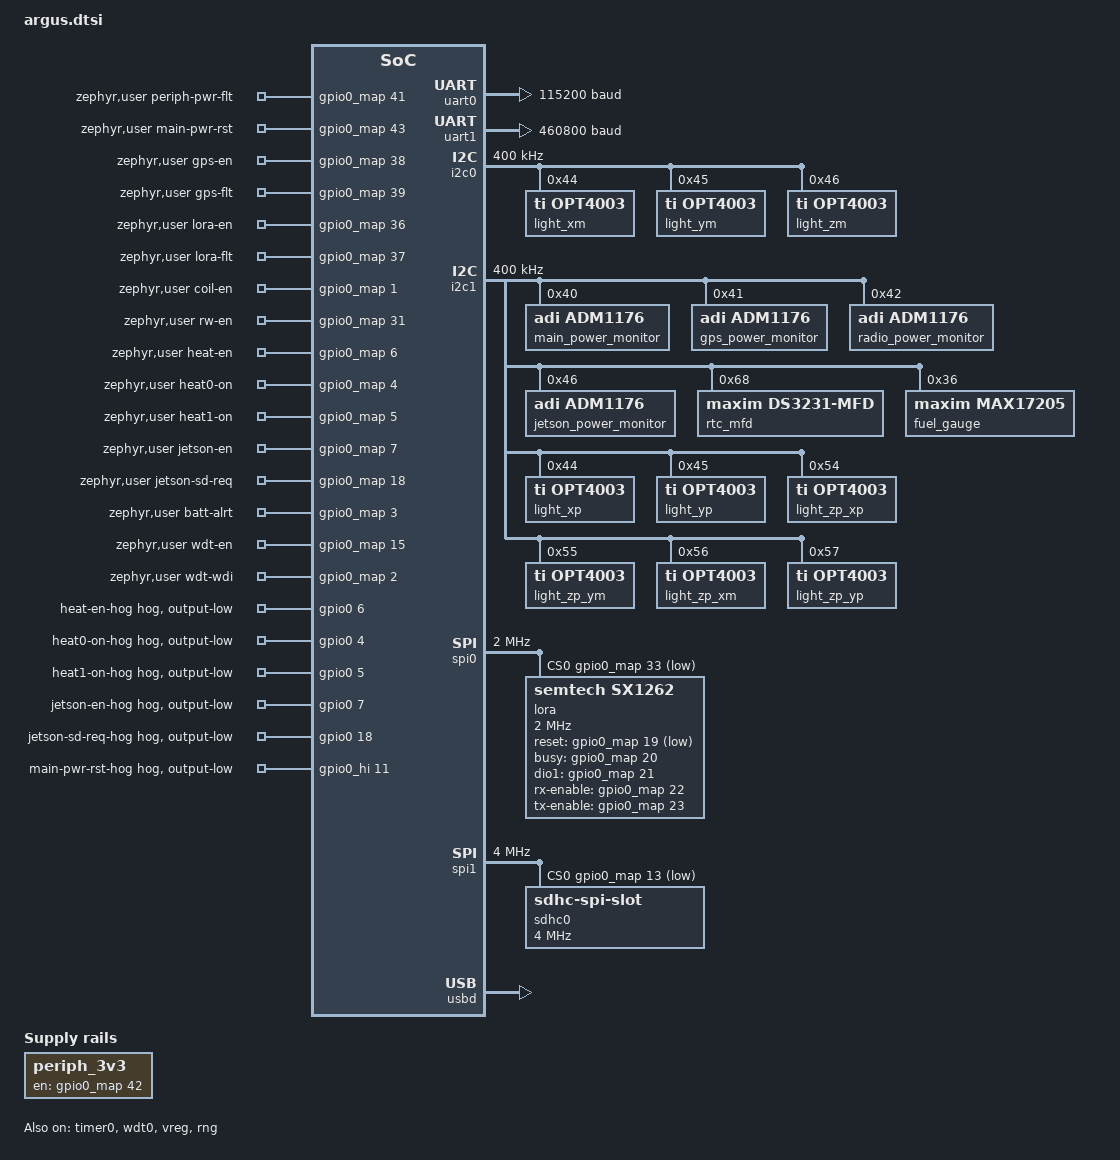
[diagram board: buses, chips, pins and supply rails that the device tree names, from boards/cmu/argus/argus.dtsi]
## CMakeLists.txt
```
cmake_minimum_required(VERSION 3.20.0)

# Default target (current default hardware revision is set in boards/cmu/argus/board.yml).
# Pick a revision explicitly with e.g. `west build -b argus@4/rp2350b/m33_0`.
set(BOARD argus/rp2350b/m33_0)

list(APPEND BOARD_ROOT ${CMAKE_CURRENT_SOURCE_DIR})
find_package(Zephyr REQUIRED HINTS $ENV{ZEPHYR_BASE})
project(FSW-Mainboard-C)

target_sources(app PRIVATE
        src/main.c
        src/drivers/adm1176.c
        src/drivers/drv8235.c
        src/drivers/max17205.c
        src/drivers/opt4003.c
        src/apps/eps/eps.c
        src/tasks/eps.c
        src/tasks/eps_runner.c
)

target_include_directories(app PRIVATE
        ${CMAKE_CURRENT_LIST_DIR}/include
)

# Generate argus_version.h (git hash + dirty flag) on every build, so the
# version printed at boot is never stale.
set(ARGUS_VERSION_DIR ${CMAKE_BINARY_DIR}/include/generated/argus)
add_custom_target(argus_version_h
        COMMAND ${CMAKE_COMMAND}
                -DSRC_DIR=${CMAKE_CURRENT_SOURCE_DIR}
                -DOUT_FILE=${ARGUS_VERSION_DIR}/argus_version.h
                -P ${CMAKE_CURRENT_SOURCE_DIR}/cmake/gen_version.cmake
        BYPRODUCTS ${ARGUS_VERSION_DIR}/argus_version.h
)
add_dependencies(app argus_version_h)
target_include_directories(app PRIVATE ${ARGUS_VERSION_DIR})
```

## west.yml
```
# West manifest: pins the Zephyr version and the modules this project uses.
# Set up a workspace with:
#   west init -m https://github.com/cmu-argus-2/FSW-Mainboard-C --mr main <workspace-dir>
#   cd <workspace-dir> && west update

manifest:
  remotes:
    - name: zephyrproject-rtos
      url-base: https://github.com/zephyrproject-rtos

  projects:
    - name: zephyr
      remote: zephyrproject-rtos
      revision: 839728050444f90d06870b5fc9bbbda106d91459
      import:
        name-allowlist:
          - cmsis_6       # Cortex-M33 core support
          - hal_rpi_pico  # RP2350 drivers
          - fatfs         # SD card filesystem
          - littlefs      # on-board flash storage
          - loramac-node  # SX1262 radio backend

  self:
    path: FSW-Mainboard-C
```

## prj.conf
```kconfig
CONFIG_LED_STRIP=y
CONFIG_I2C=y
CONFIG_FUEL_GAUGE=y
CONFIG_MAIN_STACK_SIZE=4096
CONFIG_HW_STACK_PROTECTION=y
CONFIG_SENSOR=y
# The RP2350 die-temperature node is enabled by the SoC DTS, but the Argus
# board does not enable its ADC. It is unrelated to the external ADM1176s.
CONFIG_RPI_PICO_TEMP=n
CONFIG_LOG=y
```

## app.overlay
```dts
/* SPDX-License-Identifier: Apache-2.0 */
/* EPS consumes the SoC die-temperature sensor via the ADC. */
&adc {
	status = "okay";
};

&die_temp {
	status = "okay";
};
```

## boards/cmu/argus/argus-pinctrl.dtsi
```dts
/*
 * SPDX-License-Identifier: Apache-2.0
 *
 * Revision 4 pin numbers from the Python flight software's
 * firmware/Mainboard v4/pins.c (the CircuitPython board definition).
 */

#include <zephyr/dt-bindings/pinctrl/rpi-pico-rp2350b-pinctrl.h>

&pinctrl {
	/* GPS: TX0/RX0 */
	uart0_default: uart0_default {
		group1 {
			pinmux = <UART0_TX_P44>;
		};

		group2 {
			pinmux = <UART0_RX_P45>;
			input-enable;
		};
	};

	/* Jetson: TX1/RX1 */
	uart1_default: uart1_default {
		group1 {
			pinmux = <UART1_TX_P8>;
		};

		group2 {
			pinmux = <UART1_RX_P9>;
			input-enable;
		};
	};

	/* Radio. CS (GPIO33) is a plain GPIO, see cs-gpios. */
	spi0_default: spi0_default {
		group1 {
			pinmux = <SPI0_SCK_P34>, <SPI0_TX_P35>;
		};

		group2 {
			pinmux = <SPI0_RX_P32>;
			input-enable;
		};
	};

	/* SD card. CS (GPIO13) is a plain GPIO, see cs-gpios. */
	spi1_default: spi1_default {
		group1 {
			pinmux = <SPI1_SCK_P10>, <SPI1_TX_P11>;
		};

		group2 {
			pinmux = <SPI1_RX_P12>;
			input-enable;
		};
	};

	/* -X/-Y/-Z faces, IMU */
	i2c0_default: i2c0_default {
		group1 {
			pinmux = <I2C0_SDA_P24>, <I2C0_SCL_P25>;
			input-enable;
			input-schmitt-enable;
		};
	};

	/* +X/+Y/+Z faces, RTC, fuel gauge, power monitors */
	i2c1_default: i2c1_default {
		group1 {
			pinmux = <I2C1_SDA_P46>, <I2C1_SCL_P47>;
			input-enable;
			input-schmitt-enable;
		};
	};

	ws2812_pio0_default: ws2812_pio0_default {
		ws2812 {
			pinmux = <PIO0_P0>;
		};
	};
};
```

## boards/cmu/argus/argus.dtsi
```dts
/*
 * SPDX-License-Identifier: Apache-2.0
 *
 * CMU Argus Mainboard: RP2350B, W25Q32JV (4 MiB) flash.
 *
 * These base files describe revision 4. Later revisions go in
 * argus_rp2350b_m33_0_<N>.overlay (see board.yml).
 *
 * Pin numbers come from the Python flight software's
 * firmware/Mainboard v4/pins.c and bus assignments from its
 * flight/hal/argus_v4.py.
 *
 * GPIOs are referenced through &gpio0_map, which takes the raw GPIO number
 * (0-47) and routes 32-47 to the high bank, so numbers match pins.c.
 */

#include <freq.h>

#include <zephyr/dt-bindings/i2c/i2c.h>
#include <zephyr/dt-bindings/led/led.h>
#include <zephyr/dt-bindings/lora/sx126x.h>

#include "argus-pinctrl.dtsi"

/ {
	chosen {
		zephyr,sram = &sram0;
		zephyr,flash = &flash0;
		zephyr,flash-controller = &qmi;
		zephyr,code-partition = &code_partition;
	};

	aliases {
		watchdog0 = &wdt0;
		led-strip = &neopixel;
		lora0 = &lora;
		gps-uart = &uart0;
		jetson-uart = &uart1;
	};

	/*
	 * Board control lines, read with GPIO_DT_SPEC_GET(DT_PATH(zephyr_user), <prop>).
	 * Enables are active-high (the Python HAL sets them True to turn things on).
	 * *-flt-gpios and batt-alrt-gpios are described at the raw pin level;
	 * their real polarity has not been checked against the schematic.
	 */
	/* PERIPH_PWR_EN. Powers I2C0/I2C1 devices; comes up before their drivers init. */
	periph_3v3: periph-3v3 {
		compatible = "regulator-fixed";
		regulator-name = "periph_3v3";
		enable-gpios = <&gpio0_map 42 GPIO_ACTIVE_HIGH>;
		startup-delay-us = <100000>;
		regulator-boot-on;
	};

	zephyr,user {
		periph-pwr-flt-gpios = <&gpio0_map 41 GPIO_ACTIVE_HIGH>;

		/* Power-cycles the MCU rail. */
		main-pwr-rst-gpios = <&gpio0_map 43 GPIO_ACTIVE_HIGH>;

		gps-en-gpios = <&gpio0_map 38 GPIO_ACTIVE_HIGH>;
		gps-flt-gpios = <&gpio0_map 39 GPIO_ACTIVE_HIGH>;
		lora-en-gpios = <&gpio0_map 36 GPIO_ACTIVE_HIGH>;
		lora-flt-gpios = <&gpio0_map 37 GPIO_ACTIVE_HIGH>;
		coil-en-gpios = <&gpio0_map 1 GPIO_ACTIVE_HIGH>;
		rw-en-gpios = <&gpio0_map 31 GPIO_ACTIVE_HIGH>;

		heat-en-gpios = <&gpio0_map 6 GPIO_ACTIVE_HIGH>;
		heat0-on-gpios = <&gpio0_map 4 GPIO_ACTIVE_HIGH>;
		heat1-on-gpios = <&gpio0_map 5 GPIO_ACTIVE_HIGH>;

		jetson-en-gpios = <&gpio0_map 7 GPIO_ACTIVE_HIGH>;
		/* Wired to the 5V DC-DC enable, per argus_v4.py. */
		jetson-sd-req-gpios = <&gpio0_map 18 GPIO_ACTIVE_HIGH>;

		batt-alrt-gpios = <&gpio0_map 3 GPIO_ACTIVE_HIGH>;

		/*
		 * External watchdog. Driving WDT_EN high arms it; after that WDT_WDI
		 * must be toggled or the board resets. Left undriven at boot.
		 */
		wdt-en-gpios = <&gpio0_map 15 GPIO_ACTIVE_HIGH>;
		wdt-wdi-gpios = <&gpio0_map 2 GPIO_ACTIVE_HIGH>;
	};
};

&flash0 {
	reg = <0x10000000 DT_SIZE_M(4)>;
	ranges = <0x0 0x10000000 DT_SIZE_M(4)>;
	status = "okay";

	partitions {
		ranges;
		#address-cells = <0x1>;
		#size-cells = <0x1>;

		code_partition: partition@0 {
			compatible = "zephyr,mapped-partition";
			label = "code";
			reg = <0x0 DT_SIZE_M(3)>;
			read-only;
		};

		storage_partition: partition@300000 {
			compatible = "zephyr,mapped-partition";
			label = "storage";
			reg = <0x300000 DT_SIZE_M(1)>;
		};
	};
};

/* Hogs: pins held low from GPIO init, before the app runs. Bank pin = GPIO - 32 on gpio0_hi. */
gpio0_lo: &gpio0 {
	status = "okay";

	heat-en-hog {
		gpio-hog;
		gpios = <6 GPIO_ACTIVE_HIGH>;
		output-low;
	};

	heat0-on-hog {
		gpio-hog;
		gpios = <4 GPIO_ACTIVE_HIGH>;
		output-low;
	};

	heat1-on-hog {
		gpio-hog;
		gpios = <5 GPIO_ACTIVE_HIGH>;
		output-low;
	};

	jetson-en-hog {
		gpio-hog;
		gpios = <7 GPIO_ACTIVE_HIGH>;
		output-low;
	};

	jetson-sd-req-hog {
		gpio-hog;
		gpios = <18 GPIO_ACTIVE_HIGH>;
		output-low;
	};
};

&gpio0_hi {
	status = "okay";

	/* GPIO43 */
	main-pwr-rst-hog {
		gpio-hog;
		gpios = <11 GPIO_ACTIVE_HIGH>;
		output-low;
	};
};

/* GPS */
&uart0 {
	current-speed = <115200>;
	pinctrl-0 = <&uart0_default>;
	pinctrl-names = "default";
	status = "okay";
};

/* Jetson */
&uart1 {
	current-speed = <460800>;
	pinctrl-0 = <&uart1_default>;
	pinctrl-names = "default";
	status = "okay";
};

&i2c0 {
	clock-frequency = <I2C_BITRATE_FAST>;
	pinctrl-0 = <&i2c0_default>;
	pinctrl-names = "default";
	status = "okay";

	light_xm: opt4003@44 {
		compatible = "ti,opt4003";
		reg = <0x44>;
		conversion-time = <0>;
	};

	light_ym: opt4003@45 {
		compatible = "ti,opt4003";
		reg = <0x45>;
		conversion-time = <0>;
	};

	light_zm: opt4003@46 {
		compatible = "ti,opt4003";
		reg = <0x46>;
		conversion-time = <0>;
	};
};

&i2c1 {
	clock-frequency = <I2C_BITRATE_FAST>;
	pinctrl-0 = <&i2c1_default>;
	pinctrl-names = "default";
	status = "okay";

	main_power_monitor: adm1176@40 {
		compatible = "adi,adm1176";
		reg = <0x40>;
		rshunt-micro-ohms = <10000>;
		status = "okay";
	};

	gps_power_monitor: adm1176@41 {
		compatible = "adi,adm1176";
		reg = <0x41>;
		rshunt-micro-ohms = <10000>;
		status = "okay";
	};

	radio_power_monitor: adm1176@42 {
		compatible = "adi,adm1176";
		reg = <0x42>;
		rshunt-micro-ohms = <10000>;
		status = "okay";
	};

	jetson_power_monitor: adm1176@46 {
		compatible = "adi,adm1176";
		reg = <0x46>;
		rshunt-micro-ohms = <10000>;
		status = "okay";
	};

	rtc_mfd: ds3231@68 {
		compatible = "maxim,ds3231-mfd";
		reg = <0x68>;
		status = "okay";

		rtc: rtc {
			compatible = "maxim,ds3231-rtc";
			status = "okay";
		};
	};

	/* Battery board fuel gauge. Shadow RAM answers at 0x0B too (see binding). */
	fuel_gauge: max17205@36 {
      compatible = "maxim,max17205";
      reg = <0x36>;
      rsense-micro-ohms = <10000>;   /* check the schematic */
      status = "okay";
  };
      
	light_xp: opt4003@44 {
		compatible = "ti,opt4003";
		reg = <0x44>;
		conversion-time = <0>;
	};

	light_yp: opt4003@45 {
		compatible = "ti,opt4003";
		reg = <0x45>;
		conversion-time = <0>;
	};

	light_zp_xp: opt4003@54 {
		compatible = "ti,opt4003";
		reg = <0x54>;
		conversion-time = <0>;
	};

	light_zp_ym: opt4003@55 {
		compatible = "ti,opt4003";
		reg = <0x55>;
		conversion-time = <0>;
	};

	light_zp_xm: opt4003@56 {
		compatible = "ti,opt4003";
		reg = <0x56>;
		conversion-time = <0>;
	};

	light_zp_yp: opt4003@57 {
		compatible = "ti,opt4003";
		reg = <0x57>;
		conversion-time = <0>;
	};
};

&spi0 {
	clock-frequency = <DT_FREQ_M(2)>;
	pinctrl-0 = <&spi0_default>;
	pinctrl-names = "default";
	cs-gpios = <&gpio0_map 33 GPIO_ACTIVE_LOW>;
	status = "okay";

	/* Settings match the defaults used by flight/hal/drivers/sx126x.py. */
	lora: lora@0 {
		compatible = "semtech,sx1262";
		reg = <0>;
		spi-max-frequency = <DT_FREQ_M(2)>;
		reset-gpios = <&gpio0_map 19 GPIO_ACTIVE_LOW>;
		busy-gpios = <&gpio0_map 20 GPIO_ACTIVE_HIGH>;
		dio1-gpios = <&gpio0_map 21 GPIO_ACTIVE_HIGH>;
		rx-enable-gpios = <&gpio0_map 22 GPIO_ACTIVE_HIGH>;
		tx-enable-gpios = <&gpio0_map 23 GPIO_ACTIVE_HIGH>;
		dio3-tcxo-voltage = <SX126X_DIO3_TCXO_1V7>;
		tcxo-power-startup-delay-ms = <5>;
		status = "okay";
	};
};

&spi1 {
	clock-frequency = <DT_FREQ_M(4)>;
	pinctrl-0 = <&spi1_default>;
	pinctrl-names = "default";
	cs-gpios = <&gpio0_map 13 GPIO_ACTIVE_LOW>;
	status = "okay";

	sdhc0: sdhc@0 {
		compatible = "zephyr,sdhc-spi-slot";
		reg = <0>;
		spi-max-frequency = <DT_FREQ_M(4)>;
		status = "okay";

		mmc {
			compatible = "zephyr,sdmmc-disk";
			disk-name = "SD";
			status = "okay";
		};
	};
};

&pio0 {
	status = "okay";

	pio-ws2812 {
		compatible = "worldsemi,ws2812-rpi_pico-pio";
		pinctrl-0 = <&ws2812_pio0_default>;
		pinctrl-names = "default";
		bit-waveform = <3>, <3>, <4>;
		status = "okay";

		neopixel: ws2812 {
			gpios = <&gpio0_map 0 GPIO_ACTIVE_HIGH>;
			chain-length = <1>;
			color-mapping = <LED_COLOR_ID_GREEN
					 LED_COLOR_ID_RED
					 LED_COLOR_ID_BLUE>;
			reset-delay = <280>;
			frequency = <DT_FREQ_K(800)>;
			status = "okay";
		};
	};
};

&timer0 {
	status = "okay";
};

&wdt0 {
	status = "okay";
};

&vreg {
	status = "okay";
};

&rng {
	status = "okay";
};

zephyr_udc0: &usbd {
	status = "okay";
};

#include <../boards/common/usb/cdc_acm_serial.dtsi>
```

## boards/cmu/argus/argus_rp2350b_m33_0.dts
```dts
/*
 * SPDX-License-Identifier: Apache-2.0
 */

/dts-v1/;

#include <raspberrypi/rpi_pico/rp2350b.dtsi>
#include <raspberrypi/rpi_pico/m33.dtsi>
#include "argus.dtsi"
```

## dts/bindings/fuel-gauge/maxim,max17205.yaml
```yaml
# MAX17205 fuel gauge. Driven by the application (src/drivers/max17205.c),
# not by an in-tree Zephyr driver; this binding only exists so the app can get
# the gauge's bus and address with I2C_DT_SPEC_GET().
#
# reg is the main register block (0x36). The shadow RAM at 0x0B is fixed by
# the chip, so the driver derives it rather than taking it from here.

description: Maxim MAX17205 multi-cell ModelGauge m5 fuel gauge

compatible: "maxim,max17205"

properties:
  rsense-micro-ohms:
    type: int
    required: true
    description: Current-sense resistor value in micro-ohms.

include: i2c-device.yaml
```

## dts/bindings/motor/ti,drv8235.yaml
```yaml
# SPDX-License-Identifier: Apache-2.0

description: |
  Test-only DRV8235 binding for the I2C register emulator. This declares the
  properties consumed by the real driver without importing the Argus board
  library. Bus addresses, rail setup, and explicit limits belong to the test
  overlays, not this schema. Keep property types aligned with the hardware
  binding; this fixture does not validate the production board definition.

compatible: "ti,drv8235"

include: i2c-device.yaml

properties:
  vm-supply:
    type: phandle
    required: true

  max-output-microvolt:
    type: int
    required: true

  coil-resistance-milliohm:
    type: int
    required: true

  imtr-full-scale-microamp:
    type: int
    required: true
```

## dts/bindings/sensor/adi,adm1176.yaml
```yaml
# Copyright (c) 2026 Carnegie Mellon University
# SPDX-License-Identifier: Apache-2.0

description: |
  Analog Devices ADM1176 hot-swap controller and I2C power monitor.

  The device measures bus voltage and the voltage across an external shunt
  resistor with a 12-bit ADC. The driver exposes voltage and current through
  Zephyr's sensor API.

compatible: "adi,adm1176"

include: [sensor-device.yaml, i2c-device.yaml]

properties:
  rshunt-micro-ohms:
    type: int
    required: true
    description: External current-sense resistor value in micro-ohms.

  voltage-range-microvolt:
    type: int
    default: 26350000
    enum: [6650000, 26350000]
    description: |
      Full-scale bus-voltage range in microvolts. The default preserves the
      26.35 V range used by the previous Argus flight driver. Set 6650000 to
      enable the ADM1176 VRANGE bit and use the higher-resolution 6.65 V range.
```

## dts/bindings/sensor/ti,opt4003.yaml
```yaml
# Devicetree binding for the OPT4003. Each property maps to a CONFIGURATION
# register field (pages 30 and 31 of the datasheet). Defaults should match the
# constructor defaults in flight/hal/drivers/opt4003.py.

description: TI OPT4003 ambient light sensor

compatible: "ti,opt4003"

include: [sensor-device.yaml, i2c-device.yaml]

properties:
  quick-wakeup:
    type: boolean
    description: Faster wakeup from standby in one-shot mode, at higher power.

  lux-range:
    type: int
    default: 12
    enum: [0, 1, 2, 3, 4, 5, 6, 7, 8, 12]
    description: |
      0: 561 lux, 1: 1122 lux, 2: 2.2 klux, 3: 4.4 klux, 4: 8.9 klux,
      5: 17.9 klux, 6: 35.9 klux, 7: 71.8 klux, 8: 143.6 klux, 12: auto

  conversion-time:
    type: int
    default: 8
    enum: [0, 1, 2, 3, 4, 5, 6, 7, 8, 9, 10, 11]
    description: |
      0: 600us, 1: 1ms, 2: 1.8ms, 3: 3.4ms, 4: 6.5ms, 5: 12.7ms,
      6: 25ms, 7: 50ms, 8: 100ms, 9: 200ms, 10: 400ms, 11: 800ms

  transparent-hysteresis:
    type: boolean
    description: |
      Use transparent hysteresis interrupt mode. Default is latched window mode
      (pages 14 and 15 of the datasheet).

  int-active-high:
    type: boolean
    description: INT pin is active high. Default is active low.

  fault-count:
    type: int
    default: 0
    enum: [0, 1, 2, 3]
    description: |
      Consecutive faults needed to trigger the threshold mechanism.
      0: one, 1: two, 2: four, 3: eight
```

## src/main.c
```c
#include <zephyr/sys/printk.h>

#include "argus/tasks/eps.h"
#include "argus_version.h"

int main(void)
{
	printk("Argus FSW mainboard rev %s (%s)\n", CONFIG_BOARD_REVISION, ARGUS_GIT_VERSION);
	printk("EPS console-only: hardware callbacks are not connected; no peripheral access\n");
	printk("EPS 1 Hz; time is uptime seconds; full record every fifth run\n");
	eps_run(eps_console_only_io());
	return 0;
}
```
